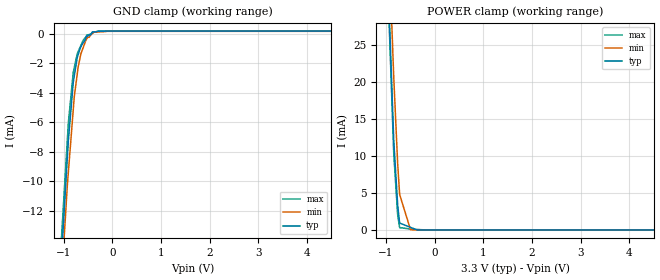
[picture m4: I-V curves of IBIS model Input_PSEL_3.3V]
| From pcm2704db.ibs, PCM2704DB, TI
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[Model] Input_PSEL_3.3V
Model_type Input
Vinl  = 800.000mV
Vinh  = 2.00000V
C_comp  2.00000pF 2.00000pF 2.00000pF
| variable   typ   min   max
[Voltage Range]   3.30000V  3.00000V  3.60000V
[POWER Clamp Reference]  3.30000V  3.00000V  3.60000V
[GND Clamp Reference]   0.00000V  0.00000V  0.00000V
[Temperature Range]   25   85   -25
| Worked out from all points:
|   GND clamp passes 1 mA (typ) near -0.66 V on its own axis
|   POWER clamp passes 1 mA (typ) near -0.72 V on its own axis
[GND Clamp]
-3.3V     -140.8mA   -139.2mA   -138.3mA
-921.7mV  -8.364mA   -10.23mA   -7.161mA
-901.3mV  -7.23mA    -9.374mA   -6.038mA
-800.6mV  -3.279mA   -5.128mA   -2.6mA
-780.4mV  -2.862mA   -4.278mA   -2.286mA
-719.6mV  -1.606mA   -2.734mA   -1.341mA
-699.5mV  -1.397mA   -2.223mA   -1.19mA
-643.7mV  -876uA     -1.341mA   -770.8uA
-542.3mV  -256.9uA   -435.1uA   -259.8uA
-405.9mV  142.7uA    36.77uA    117.8uA
-95.38mV  198.5uA    182.8uA    206.2uA
6.6V      198.5uA    182.8uA    206.2uA
[POWER Clamp]
-3.3V     465.9mA    458.7mA    514.8mA
-1.019V   44.81mA    52.21mA    43.33mA
-842.3mV  12.17mA    20.7mA     10.38mA
-761.5mV  3.389mA    8.982mA    2.054mA
-721.2mV  933.5uA    4.804mA    318.7uA
-498mV    355.7uA    48.92uA    133uA
-360.6mV  0A         0A         69.66uA
6.6V      0A         0A         0A
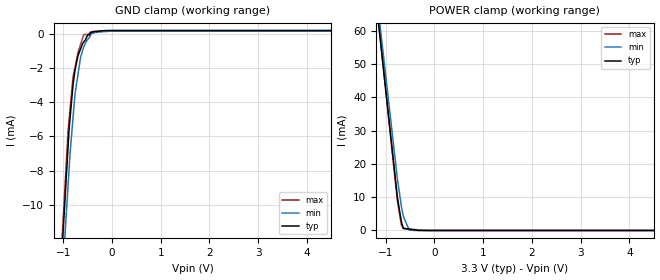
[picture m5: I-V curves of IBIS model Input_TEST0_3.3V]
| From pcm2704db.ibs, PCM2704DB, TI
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[Model] Input_TEST0_3.3V
Model_type Input
Vinl  = 800.000mV
Vinh  = 2.00000V
C_comp  2.00000pF 2.00000pF 2.00000pF
| variable   typ   min   max
[Voltage Range]   3.30000V  3.00000V  3.60000V
[POWER Clamp Reference]  3.30000V  3.00000V  3.60000V
[GND Clamp Reference]   0.00000V  0.00000V  0.00000V
[Temperature Range]   25   85   -25
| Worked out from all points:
|   GND clamp passes 1 mA (typ) near -0.66 V on its own axis
|   POWER clamp passes 1 mA (typ) near -0.65 V on its own axis
[GND Clamp]
-3.3V     -124.7mA   -119.3mA   -128.4mA
-901.3mV  -6.571mA   -8.863mA   -5.667mA
-881.1mV  -5.577mA   -7.934mA   -5.039mA
-861.1mV  -4.935mA   -7.015mA   -4.417mA
-800.5mV  -2.988mA   -4.931mA   -2.53mA
-760.1mV  -2.122mA   -3.541mA   -1.96mA
-699.4mV  -1.282mA   -2.4mA     -1.106mA
-643.8mV  -860.6uA   -1.353mA   -601.6uA
-580.5mV  -467.7uA   -757uA     -28.33uA
-421.2mV  94.21uA    52.16uA    143.9uA
-66.12mV  207.3uA    167.2uA    176.8uA
6.6V      209.8uA    167.2uA    176.8uA
[POWER Clamp]
-3.3V     352.4mA    343.7mA    367.6mA
-1.08V    52.9mA     56.66mA    53.18mA
-958.6mV  36.57mA    41mA       36.03mA
-761.5mV  9.983mA    15.52mA    8.882mA
-680.5mV  2.623mA    7.332mA    1.712mA
-640.2mV  655.4uA    4.295mA    570.9uA
-518.3mV  405.8uA    116.5uA    419.9uA
-402.2mV  168.1uA    0A         276.1uA
-120.3mV  0A         0A         0A
6.6V      0A         0A         0A
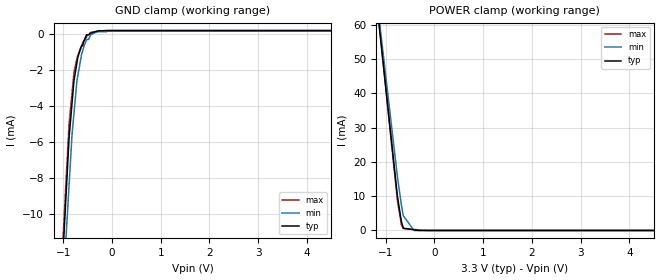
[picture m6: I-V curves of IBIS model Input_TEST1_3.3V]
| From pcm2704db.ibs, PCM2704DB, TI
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[Model] Input_TEST1_3.3V
Model_type Input
Vinl  = 800.000mV
Vinh  = 2.00000V
C_comp  2.00000pF 2.00000pF 2.00000pF
| variable   typ   min   max
[Voltage Range]   3.30000V  3.00000V  3.60000V
[POWER Clamp Reference]  3.30000V  3.00000V  3.60000V
[GND Clamp Reference]   0.00000V  0.00000V  0.00000V
[Temperature Range]   25   85   -25
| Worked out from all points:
|   GND clamp passes 1 mA (typ) near -0.67 V on its own axis
|   POWER clamp passes 1 mA (typ) near -0.65 V on its own axis
[GND Clamp]
-3.3V     -130.1mA   -120.2mA   -129.1mA
-881.1mV  -5.749mA   -8.392mA   -4.971mA
-820.9mV  -3.852mA   -5.606mA   -3.263mA
-780.4mV  -2.576mA   -4.398mA   -2.114mA
-719.6mV  -1.585mA   -2.584mA   -1.338mA
-699.4mV  -1.257mA   -2.276mA   -1.172mA
-623.6mV  -651uA     -1.115mA   -627.6uA
-522.1mV  -31.22uA   -324.1uA   -152.3uA
-479.1mV  -25.74uA   -291.7uA   -28.83uA
-441.3mV  53.78uA    -38.8uA    97.82uA
-30.79mV  207.9uA    173.6uA    180.3uA
6.6V      207.9uA    173.6uA    180.3uA
[POWER Clamp]
-3.3V     347.9mA    327.9mA    363.9mA
-1.08V    52.38mA    54.86mA    52.67mA
-958.6mV  36.26mA    39.97mA    35.7mA
-761.5mV  10.02mA    15.73mA    8.83mA
-680.5mV  2.655mA    7.556mA    1.705mA
-640.2mV  669.7uA    4.332mA    552.3uA
-422.1mV  213.4uA    904.5nA    290.9uA
-120.3mV  0A         0A         0A
6.6V      0A         0A         0A
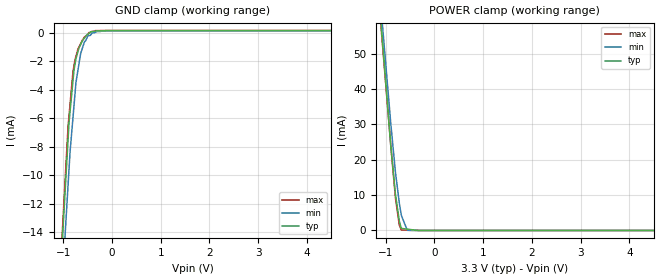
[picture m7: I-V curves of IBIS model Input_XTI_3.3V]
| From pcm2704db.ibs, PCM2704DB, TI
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[Model] Input_XTI_3.3V
Model_type Input
Vinl  = 800.000mV
Vinh  = 2.00000V
C_comp  2.00000pF 2.00000pF 2.00000pF
| variable   typ   min   max
[Voltage Range]   3.30000V  3.00000V  3.60000V
[POWER Clamp Reference]  3.30000V  3.00000V  3.60000V
[GND Clamp Reference]   0.00000V  0.00000V  0.00000V
[Temperature Range]   25   85   -25
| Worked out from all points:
|   GND clamp passes 1 mA (typ) near -0.67 V on its own axis
|   POWER clamp passes 1 mA (typ) near -0.69 V on its own axis
[GND Clamp]
-3.3V     -152.1mA   -148.1mA   -157.5mA
-901.3mV  -7.472mA   -10.69mA   -6.553mA
-881.1mV  -6.256mA   -9.536mA   -5.788mA
-861.1mV  -5.536mA   -8.39mA    -5.029mA
-800.5mV  -3.353mA   -5.942mA   -2.73mA
-780.4mV  -2.627mA   -5.128mA   -2.323mA
-739.7mV  -1.807mA   -3.484mA   -1.654mA
-643.7mV  -820.9uA   -1.452mA   -762.3uA
-562.2mV  -345uA     -602.3uA   -275.1uA
-416mV    83.3uA     -47.86uA   108.5uA
-91.58mV  164.2uA    149.3uA    170.6uA
6.6V      164.4uA    149.3uA    170.6uA
[POWER Clamp]
-3.3V     439.7mA    421.3mA    426.6mA
-1.12V    62.51mA    66.56mA    61.4mA
-1.039V   48.51mA    53.39mA    47.85mA
-897.8mV  24.04mA    30.38mA    24.16mA
-802.1mV  10.34mA    16.56mA    9.259mA
-721.2mV  2.588mA    7.664mA    1.467mA
-680.5mV  582.9uA    4.273mA    140.8uA
-559.2mV  375.1uA    64.49uA    60.06uA
-340.2mV  0A         0A         24.51uA
6.6V      0A         0A         0A
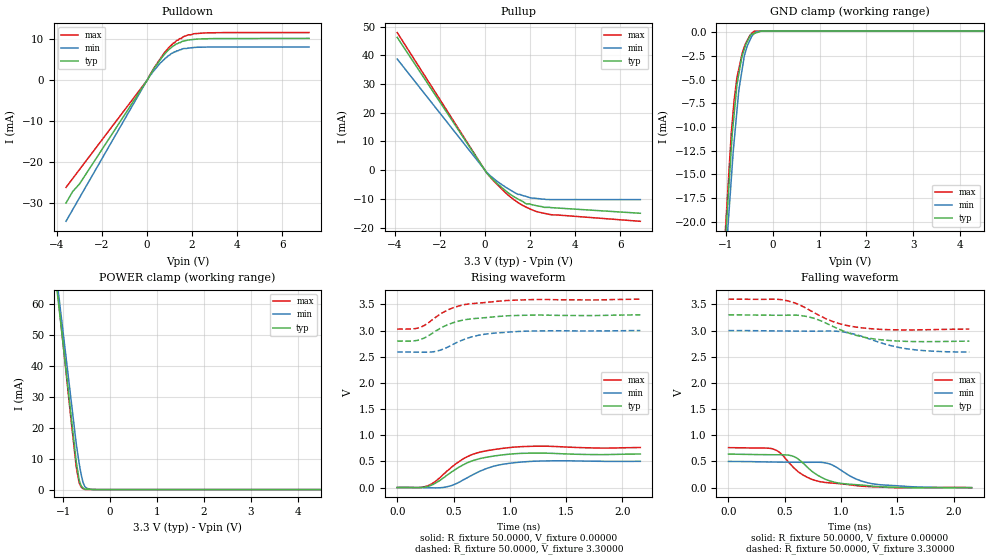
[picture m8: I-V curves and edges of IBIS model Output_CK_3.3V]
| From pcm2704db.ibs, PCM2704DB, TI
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[Model] Output_CK_3.3V
Model_type Output
Vref  = 0.00000V
Cref  = 2.00000pF
Vmeas = 1.65000V
C_comp  2.00000pF 2.00000pF 2.00000pF
| variable   typ   min   max
[Voltage Range]   3.30000V  3.00000V  3.60000V
[POWER Clamp Reference]  3.30000V  3.00000V  3.60000V
[Pullup Reference]   3.30000V  3.00000V  3.60000V
[Pulldown Reference]   0.00000V  0.00000V  0.00000V
[GND Clamp Reference]   0.00000V  0.00000V  0.00000V
[Temperature Range]   25   85   -25
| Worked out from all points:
|   slope of the pulldown table from 0 to 0.495 V, typ, clamps not added: 114 ohm
|   slope of the pullup table from 0 to 0.495 V, typ, clamps not added: 116 ohm
|   GND clamp passes 1 mA (typ) near -0.55 V on its own axis
|   POWER clamp passes 1 mA (typ) near -0.60 V on its own axis
|   rising waveform, R_fixture 50.0000, V_fixture 0.00000: 20-80 % time 296ps typ, 298ps min, 286ps max; typ from 0 V to 0.64 V
|   falling waveform, R_fixture 50.0000, V_fixture 0.00000: 20-80 % time 263ps typ, 275ps min, 265ps max; typ from 0.64 V to 0 V
|   falling waveform, R_fixture 50.0000, V_fixture 3.30000: 20-80 % time 347ps typ, 388ps min, 335ps max; typ from 3.3 V to 2.8 V
|   rising waveform, R_fixture 50.0000, V_fixture 3.30000: 20-80 % time 312ps typ, 307ps min, 303ps max; typ from 2.8 V to 3.3 V
[GND Clamp]
-3.3V     -198.8mA   -187mA     -207.8mA
-881.1mV  -12.31mA   -15.49mA   -10.64mA
-861.1mV  -10.77mA   -14.08mA   -9.489mA
-820.8mV  -8.675mA   -11.56mA   -7.169mA
-760.1mV  -5.523mA   -8.271mA   -4.759mA
-719.6mV  -4.376mA   -6.078mA   -3.836mA
-659mV    -2.662mA   -4.201mA   -2.457mA
-603.2mV  -1.796mA   -2.471mA   -1.534mA
-461.8mV  -223.6uA   -588.8uA   -189.1uA
-390.9mV  -110.6uA   -114.1uA   123uA
-110.6mV  144.4uA    171uA      162.2uA
6.6V      144.4uA    171uA      168.5uA
[Pulldown]
-3.6V     -29.93mA   -34.38mA   -26.13mA
-3.3V     -27.11mA   -31.52mA   -23.96mA
-3V       -25.3mA    -28.66mA   -21.79mA
20.8mV    92.19uA    132.4uA    70.78uA
299.7mV   2.737mA    2.231mA    2.811mA
800.2mV   6.424mA    5.253mA    6.883mA
941.6mV   7.269mA    5.945mA    7.724mA
1.179V    8.327mA    6.76mA     9.042mA
1.442V    9.105mA    7.336mA    10.09mA
2.079V    9.887mA    7.918mA    11.27mA
3.499V    10.1mA     8.032mA    11.56mA
7.2V      10.15mA    8.034mA    11.56mA
[Pullup]
-3.9V     46.25mA    38.7mA     47.92mA
77.9mV    -979.7uA   -778.3uA   -1.01mA
518.1mV   -4.475mA   -3.764mA   -4.807mA
1.079V    -8.156mA   -6.694mA   -9.023mA
1.459V    -10.03mA   -8.412mA   -11.24mA
1.83V     -11.72mA   -9.138mA   -12.89mA
1.979V    -11.72mA   -9.527mA   -13.42mA
2.297V    -12.39mA   -9.851mA   -14.42mA
2.899V    -13.01mA   -10.22mA   -15.45mA
6.9V      -14.99mA   -10.22mA   -17.79mA
[POWER Clamp]
-3.3V     358.2mA    346.1mA    380.2mA
-1.039V   52.01mA    55.59mA    52.39mA
-842.3mV  25.32mA    30.27mA    23.83mA
-721.1mV  8.907mA    14.7mA     7.145mA
-660.2mV  3.154mA    8.48mA     2.208mA
-619.9mV  1.299mA    5.074mA    839uA
-579.2mV  517uA      2.386mA    287uA
-538.6mV  143.5uA    950.4uA    53uA
-498mV    121.8uA    421.7uA    47.85uA
-381.7mV  59.89uA    0A         33.08uA
6.6V      0A         0A         0A
[Rising Waveform]
R_fixture = 50.0000
V_fixture = 0.00000
V_fixture_min = 0.00000
V_fixture_max = 0.00000
0s        0V         0V         0V
200ps     -1.758mV   -1.258mV   662uV
280ps     26.18mV    -4.232mV   41.31mV
440ps     231.7mV    12.93mV    310.7mV
580ps     426.6mV    137.2mV    540.7mV
680ps     519.7mV    253.5mV    641.9mV
800ps     581.3mV    368.8mV    704.8mV
940ps     624.4mV    445mV      749.3mV
1.2ns     656.8mV    500.8mV    787.6mV
2.16ns    640.5mV    500.6mV    764.5mV
[Falling Waveform]
R_fixture = 50.0000
V_fixture = 0.00000
V_fixture_min = 0.00000
V_fixture_max = 0.00000
0s        640.5mV    500.6mV    764.5mV
400ps     628.4mV    489.5mV    736.3mV
460ps     628mV      488mV      662.5mV
580ps     595mV      485.5mV    380mV
700ps     393.2mV    484.4mV    198.4mV
820ps     204.2mV    484.2mV    112.2mV
980ps     88.3mV     361.2mV    77.92mV
1.14ns    55.92mV    160mV      38.05mV
1.28ns    28.99mV    74.69mV    18.1mV
2.16ns    0V         0V         0V
[Falling Waveform]
R_fixture = 50.0000
V_fixture = 3.30000
V_fixture_min = 3.00000
V_fixture_max = 3.60000
0s        3.3V       3V         3.6V
460ps     3.292V     2.992V     3.592V
560ps     3.295V     2.99V      3.547V
680ps     3.274V     2.988V     3.439V
780ps     3.219V     2.988V     3.319V
920ps     3.087V     2.991V     3.178V
1.18ns    2.884V     2.894V     3.053V
1.4ns     2.815V     2.736V     3.019V
1.58ns    2.793V     2.654V     3.011V
2.14ns    2.798V     2.59V      3.027V
[Rising Waveform]
R_fixture = 50.0000
V_fixture = 3.30000
V_fixture_min = 3.00000
V_fixture_max = 3.60000
0s        2.798V     2.59V      3.027V
120ps     2.799V     2.589V     3.029V
200ps     2.823V     2.586V     3.057V
260ps     2.879V     2.586V     3.122V
340ps     2.989V     2.601V     3.25V
480ps     3.136V     2.718V     3.421V
640ps     3.218V     2.864V     3.509V
800ps     3.249V     2.937V     3.54V
1.12ns    3.291V     2.986V     3.586V
2.16ns    3.3V       3V         3.6V
[Ramp]
| variable typ   min   max
dV/dt_r   385.913m/420.508p  299.431m/472.835p  458.492m/391.970p
dV/dt_f   303.401m/426.304p  240.705m/473.539p  346.365m/394.914p
R_load  =  50.0000Ohms
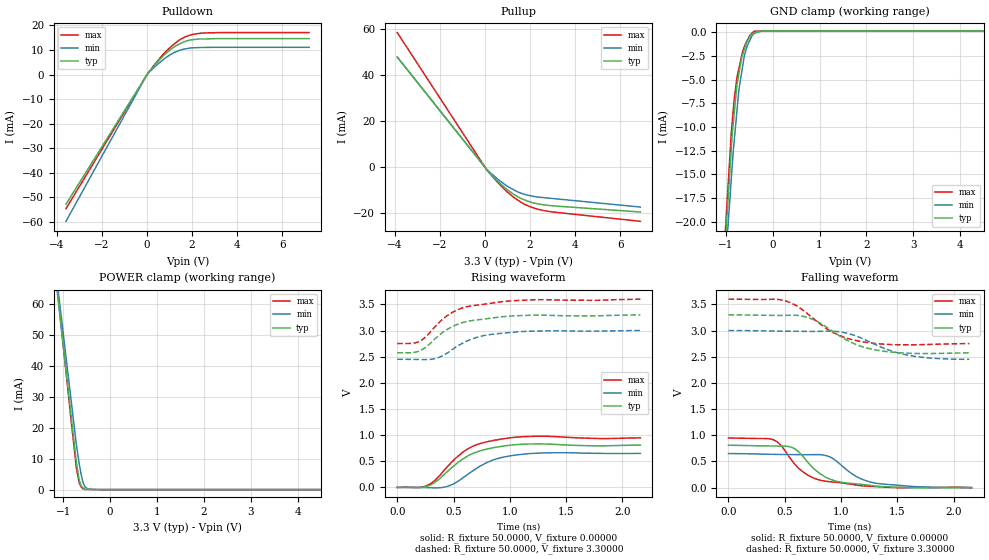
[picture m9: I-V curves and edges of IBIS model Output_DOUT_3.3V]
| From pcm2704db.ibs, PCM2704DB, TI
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[Model] Output_DOUT_3.3V
Model_type Output
Vref  = 0.00000V
Cref  = 2.00000pF
Vmeas = 1.65000V
C_comp  2.00000pF 2.00000pF 2.00000pF
| variable   typ   min   max
[Voltage Range]   3.30000V  3.00000V  3.60000V
[POWER Clamp Reference]  3.30000V  3.00000V  3.60000V
[Pullup Reference]   3.30000V  3.00000V  3.60000V
[Pulldown Reference]   0.00000V  0.00000V  0.00000V
[GND Clamp Reference]   0.00000V  0.00000V  0.00000V
[Temperature Range]   25   85   -25
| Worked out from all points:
|   slope of the pulldown table from 0 to 0.495 V, typ, clamps not added: 91 ohm
|   slope of the pullup table from 0 to 0.495 V, typ, clamps not added: 93 ohm
|   GND clamp passes 1 mA (typ) near -0.55 V on its own axis
|   POWER clamp passes 1 mA (typ) near -0.60 V on its own axis
|   rising waveform, R_fixture 50.0000, V_fixture 0.00000: 20-80 % time 296ps typ, 298ps min, 286ps max; typ from 0 V to 0.81 V
|   falling waveform, R_fixture 50.0000, V_fixture 0.00000: 20-80 % time 263ps typ, 275ps min, 265ps max; typ from 0.81 V to 0 V
|   falling waveform, R_fixture 50.0000, V_fixture 3.30000: 20-80 % time 347ps typ, 388ps min, 335ps max; typ from 3.3 V to 2.57 V
|   rising waveform, R_fixture 50.0000, V_fixture 3.30000: 20-80 % time 312ps typ, 307ps min, 303ps max; typ from 2.57 V to 3.3 V
[GND Clamp]
-3.3V     -198.8mA   -187mA     -207.8mA
-881.1mV  -12.31mA   -15.49mA   -10.64mA
-861.1mV  -10.77mA   -14.08mA   -9.489mA
-820.8mV  -8.675mA   -11.56mA   -7.169mA
-760.1mV  -5.523mA   -8.271mA   -4.759mA
-719.6mV  -4.376mA   -6.078mA   -3.836mA
-659mV    -2.662mA   -4.201mA   -2.457mA
-603.2mV  -1.796mA   -2.471mA   -1.534mA
-461.8mV  -223.6uA   -588.8uA   -189.1uA
-390.9mV  -110.6uA   -114.1uA   123uA
-110.6mV  144.4uA    171uA      162.2uA
6.6V      144.4uA    171uA      168.5uA
[Pulldown]
-3.6V     -52.77mA   -59.72mA   -54.59mA
186.8uV   -32.36uA   39.2uA     -24.78uA
340.3mV   3.865mA    3.081mA    4.108mA
800.3mV   8.288mA    6.674mA    9.033mA
1.119V    10.71mA    8.531mA    11.8mA
1.523V    12.81mA    10.07mA    14.55mA
1.78V     13.78mA    10.59mA    15.65mA
2.261V    14.44mA    10.97mA    16.72mA
3.317V    14.63mA    11.1mA     17.09mA
7.2V      14.63mA    11.1mA     17.1mA
[Pullup]
-3.9V     47.66mA    47.79mA    58.36mA
77.7mV    -1.111mA   -954.5uA   -1.163mA
761.3mV   -7.948mA   -6.718mA   -8.61mA
1.281V    -11.86mA   -9.89mA    -13.18mA
1.661V    -13.88mA   -11.54mA   -15.64mA
1.938V    -14.91mA   -12.28mA   -16.94mA
2.621V    -16.41mA   -13.28mA   -18.9mA
6.9V      -19.51mA   -17.35mA   -23.53mA
[POWER Clamp]
-3.3V     358.2mA    346.1mA    380.2mA
-1.039V   52.01mA    55.59mA    52.39mA
-842.3mV  25.32mA    30.27mA    23.83mA
-721.1mV  8.907mA    14.7mA     7.145mA
-660.2mV  3.154mA    8.48mA     2.208mA
-619.9mV  1.299mA    5.074mA    839uA
-579.2mV  517uA      2.386mA    287uA
-538.6mV  143.5uA    950.4uA    53uA
-498mV    121.8uA    421.7uA    47.85uA
-381.7mV  59.89uA    0A         33.08uA
6.6V      0A         0A         0A
[Rising Waveform]
R_fixture = 50.0000
V_fixture = 0.00000
V_fixture_min = 0.00000
V_fixture_max = 0.00000
0s        0V         0V         0V
200ps     -2.222mV   -1.634mV   820.6uV
280ps     33.09mV    -5.496mV   51.21mV
440ps     292.8mV    16.79mV    385.2mV
580ps     539.2mV    178.1mV    670.3mV
680ps     657mV      329.1mV    795.8mV
800ps     734.8mV    478.8mV    873.8mV
940ps     789.3mV    577.9mV    928.9mV
1.2ns     830.2mV    650.2mV    976.5mV
2.16ns    809.6mV    650mV      947.8mV
[Falling Waveform]
R_fixture = 50.0000
V_fixture = 0.00000
V_fixture_min = 0.00000
V_fixture_max = 0.00000
0s        809.6mV    650mV      947.8mV
400ps     794.3mV    635.6mV    912.7mV
460ps     793.8mV    633.6mV    821.4mV
580ps     752.1mV    630.4mV    471.1mV
700ps     497mV      629mV      246mV
820ps     258.1mV    628.7mV    139.1mV
980ps     111.6mV    469mV      96.6mV
1.14ns    70.68mV    207.7mV    47.18mV
1.28ns    36.65mV    96.98mV    22.44mV
2.16ns    0V         0V         0V
[Falling Waveform]
R_fixture = 50.0000
V_fixture = 3.30000
V_fixture_min = 3.00000
V_fixture_max = 3.60000
0s        3.3V       3V         3.6V
420ps     3.289V     2.99V      3.597V
520ps     3.29V      2.988V     3.555V
620ps     3.288V     2.985V     3.453V
760ps     3.204V     2.983V     3.219V
980ps     2.907V     2.978V     2.91V
1.18ns    2.698V     2.857V     2.789V
1.4ns     2.599V     2.646V     2.738V
1.58ns    2.568V     2.535V     2.727V
2.14ns    2.575V     2.45V      2.75V
[Rising Waveform]
R_fixture = 50.0000
V_fixture = 3.30000
V_fixture_min = 3.00000
V_fixture_max = 3.60000
0s        2.575V     2.45V      2.75V
120ps     2.575V     2.448V     2.753V
200ps     2.61V      2.445V     2.795V
260ps     2.692V     2.444V     2.891V
340ps     2.85V      2.465V     3.081V
480ps     3.063V     2.622V     3.334V
640ps     3.182V     2.818V     3.465V
800ps     3.227V     2.915V     3.511V
1.12ns    3.287V     2.982V     3.579V
2.16ns    3.3V       3V         3.6V
[Ramp]
| variable typ   min   max
dV/dt_r   485.428m/420.508p  391.096m/472.835p  568.419m/391.970p
dV/dt_f   437.666m/426.304p  331.922m/473.539p  510.586m/394.914p
R_load  =  50.0000Ohms
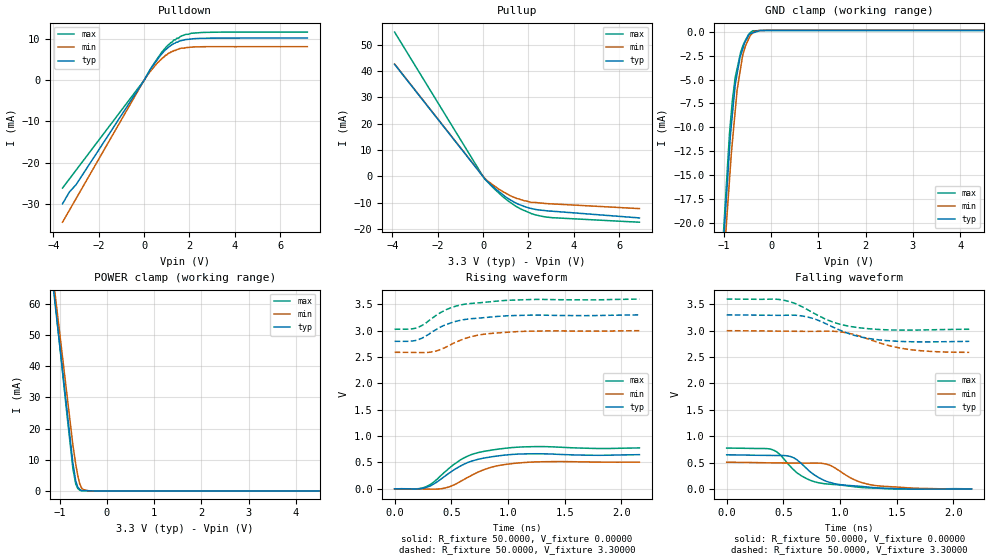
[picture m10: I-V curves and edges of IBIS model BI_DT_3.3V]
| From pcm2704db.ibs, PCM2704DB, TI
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[Model] BI_DT_3.3V
Model_type I/O
Vinl  = 800.000mV
Vinh  = 2.00000V
Vref  = 0.00000V
Cref  = 2.00000pF
Vmeas = 1.65000V
C_comp  2.00000pF 2.00000pF 2.00000pF
| variable   typ   min   max
[Voltage Range]   3.30000V  3.00000V  3.60000V
[POWER Clamp Reference]  3.30000V  3.00000V  3.60000V
[Pullup Reference]   3.30000V  3.00000V  3.60000V
[Pulldown Reference]   0.00000V  0.00000V  0.00000V
[GND Clamp Reference]   0.00000V  0.00000V  0.00000V
[Temperature Range]   25   85   -25
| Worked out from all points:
|   slope of the pulldown table from 0 to 0.495 V, typ, clamps not added: 114 ohm
|   slope of the pullup table from 0 to 0.495 V, typ, clamps not added: 116 ohm
|   GND clamp passes 1 mA (typ) near -0.55 V on its own axis
|   POWER clamp passes 1 mA (typ) near -0.60 V on its own axis
|   rising waveform, R_fixture 50.0000, V_fixture 0.00000: 20-80 % time 296ps typ, 298ps min, 286ps max; typ from 0 V to 0.648 V
|   falling waveform, R_fixture 50.0000, V_fixture 0.00000: 20-80 % time 263ps typ, 275ps min, 265ps max; typ from 0.648 V to 0 V
|   falling waveform, R_fixture 50.0000, V_fixture 3.30000: 20-80 % time 347ps typ, 388ps min, 335ps max; typ from 3.3 V to 2.8 V
|   rising waveform, R_fixture 50.0000, V_fixture 3.30000: 20-80 % time 312ps typ, 307ps min, 303ps max; typ from 2.8 V to 3.3 V
[GND Clamp]
-3.3V     -198.8mA   -187mA     -207.8mA
-881.1mV  -12.31mA   -15.49mA   -10.64mA
-861.1mV  -10.77mA   -14.08mA   -9.489mA
-820.8mV  -8.675mA   -11.56mA   -7.169mA
-760.1mV  -5.523mA   -8.271mA   -4.759mA
-719.6mV  -4.376mA   -6.078mA   -3.836mA
-659mV    -2.662mA   -4.201mA   -2.457mA
-603.2mV  -1.796mA   -2.471mA   -1.534mA
-461.8mV  -223.6uA   -588.8uA   -189.1uA
-390.9mV  -110.6uA   -114.1uA   123uA
-110.6mV  144.4uA    171uA      162.2uA
6.6V      144.4uA    171uA      168.5uA
[Pulldown]
-3.6V     -29.93mA   -34.38mA   -26.13mA
-3.3V     -27.11mA   -31.52mA   -23.96mA
-3V       -25.3mA    -28.66mA   -21.79mA
20.8mV    92.19uA    132.4uA    70.78uA
299.7mV   2.737mA    2.231mA    2.811mA
800.2mV   6.424mA    5.253mA    6.883mA
941.6mV   7.269mA    5.945mA    7.724mA
1.179V    8.327mA    6.76mA     9.042mA
1.442V    9.105mA    7.336mA    10.09mA
2.079V    9.887mA    7.918mA    11.27mA
3.499V    10.1mA     8.032mA    11.56mA
7.2V      10.15mA    8.034mA    11.56mA
[Pullup]
-3.9V     42.53mA    42.65mA    54.78mA
0V        -82.33uA   20.74uA    -14.22uA
179.3mV   -1.837mA   -1.58mA    -1.929mA
478.1mV   -4.227mA   -3.543mA   -4.596mA
1.039V    -8.041mA   -6.567mA   -8.869mA
1.459V    -10.16mA   -8.298mA   -11.43mA
1.79V     -11.41mA   -9.183mA   -12.89mA
2.257V    -12.47mA   -9.921mA   -14.51mA
2.778V    -13.05mA   -10.35mA   -15.46mA
6.9V      -15.8mA    -12.27mA   -17.43mA
[POWER Clamp]
-3.3V     358.2mA    346.1mA    380.2mA
-1.039V   52.01mA    55.59mA    52.39mA
-842.3mV  25.32mA    30.27mA    23.83mA
-721.1mV  8.907mA    14.7mA     7.145mA
-660.2mV  3.154mA    8.48mA     2.208mA
-619.9mV  1.299mA    5.074mA    839uA
-579.2mV  517uA      2.386mA    287uA
-538.6mV  143.5uA    950.4uA    53uA
-498mV    121.8uA    421.7uA    47.85uA
-381.7mV  59.89uA    0A         33.08uA
6.6V      0A         0A         0A
[Rising Waveform]
R_fixture = 50.0000
V_fixture = 0.00000
V_fixture_min = 0.00000
V_fixture_max = 0.00000
0s        0V         0V         0V
200ps     -1.778mV   -1.272mV   671.5uV
280ps     26.47mV    -4.28mV    41.9mV
440ps     234.3mV    13.08mV    315.2mV
580ps     431.4mV    138.7mV    548.5mV
680ps     525.6mV    256.3mV    651.2mV
800ps     587.8mV    372.9mV    715mV
940ps     631.5mV    450.1mV    760.2mV
1.2ns     664.2mV    506.4mV    799.1mV
2.16ns    647.7mV    506.2mV    775.6mV
[Falling Waveform]
R_fixture = 50.0000
V_fixture = 0.00000
V_fixture_min = 0.00000
V_fixture_max = 0.00000
0s        647.7mV    506.2mV    775.6mV
400ps     635.4mV    495mV      746.9mV
460ps     635mV      493.5mV    672.1mV
580ps     601.7mV    490.9mV    385.5mV
700ps     397.6mV    489.9mV    201.3mV
820ps     206.5mV    489.6mV    113.8mV
980ps     89.29mV    365.3mV    79.05mV
1.14ns    56.55mV    161.8mV    38.61mV
1.28ns    29.32mV    75.53mV    18.37mV
2.16ns    0V         0V         0V
[Falling Waveform]
R_fixture = 50.0000
V_fixture = 3.30000
V_fixture_min = 3.00000
V_fixture_max = 3.60000
0s        3.3V       3V         3.6V
460ps     3.292V     2.992V     3.592V
560ps     3.295V     2.99V      3.547V
680ps     3.274V     2.988V     3.439V
780ps     3.219V     2.988V     3.319V
920ps     3.087V     2.991V     3.178V
1.18ns    2.884V     2.894V     3.053V
1.4ns     2.815V     2.736V     3.019V
1.58ns    2.793V     2.654V     3.011V
2.14ns    2.798V     2.59V      3.027V
[Rising Waveform]
R_fixture = 50.0000
V_fixture = 3.30000
V_fixture_min = 3.00000
V_fixture_max = 3.60000
0s        2.798V     2.59V      3.027V
120ps     2.799V     2.589V     3.029V
200ps     2.823V     2.586V     3.057V
260ps     2.879V     2.586V     3.122V
340ps     2.989V     2.601V     3.25V
480ps     3.136V     2.718V     3.421V
640ps     3.218V     2.864V     3.509V
800ps     3.249V     2.937V     3.54V
1.12ns    3.291V     2.986V     3.586V
2.16ns    3.3V       3V         3.6V
[Ramp]
| variable typ   min   max
dV/dt_r   386.302m/420.508p  302.371m/472.835p  463.460m/391.970p
dV/dt_f   303.967m/426.304p  240.198m/473.539p  345.648m/394.914p
R_load  =  50.0000Ohms
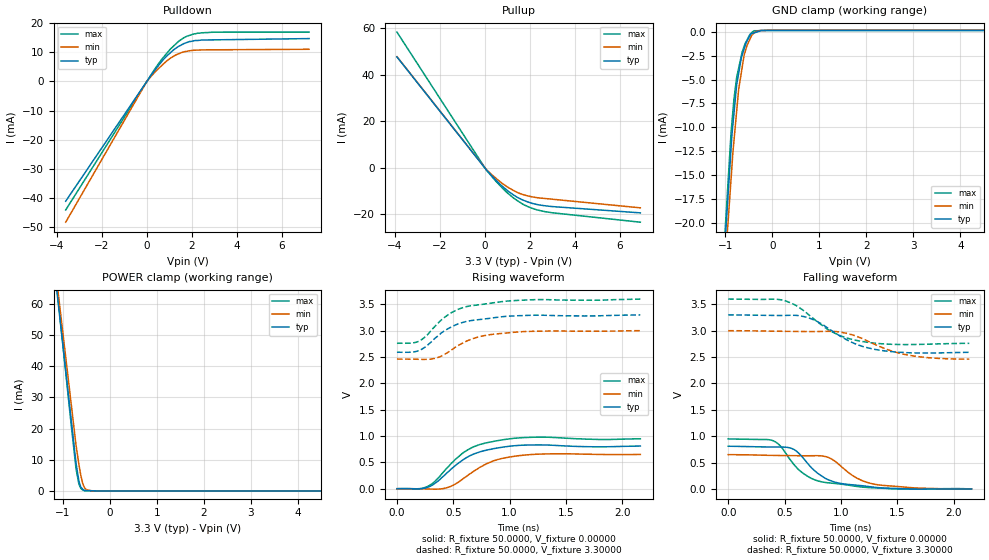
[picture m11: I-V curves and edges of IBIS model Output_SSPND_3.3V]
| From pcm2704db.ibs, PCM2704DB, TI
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[Model] Output_SSPND_3.3V
Model_type Output
Vref  = 0.00000V
Cref  = 2.00000pF
Vmeas = 1.65000V
C_comp  2.00000pF 2.00000pF 2.00000pF
| variable   typ   min   max
[Voltage Range]   3.30000V  3.00000V  3.60000V
[POWER Clamp Reference]  3.30000V  3.00000V  3.60000V
[Pullup Reference]   3.30000V  3.00000V  3.60000V
[Pulldown Reference]   0.00000V  0.00000V  0.00000V
[GND Clamp Reference]   0.00000V  0.00000V  0.00000V
[Temperature Range]   25   85   -25
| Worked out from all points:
|   slope of the pulldown table from 0 to 0.495 V, typ, clamps not added: 94.8 ohm
|   slope of the pullup table from 0 to 0.495 V, typ, clamps not added: 93 ohm
|   GND clamp passes 1 mA (typ) near -0.55 V on its own axis
|   POWER clamp passes 1 mA (typ) near -0.60 V on its own axis
|   rising waveform, R_fixture 50.0000, V_fixture 0.00000: 20-80 % time 296ps typ, 298ps min, 286ps max; typ from 0 V to 0.81 V
|   falling waveform, R_fixture 50.0000, V_fixture 0.00000: 20-80 % time 263ps typ, 275ps min, 265ps max; typ from 0.81 V to 0 V
|   falling waveform, R_fixture 50.0000, V_fixture 3.30000: 20-80 % time 347ps typ, 388ps min, 335ps max; typ from 3.3 V to 2.59 V
|   rising waveform, R_fixture 50.0000, V_fixture 3.30000: 20-80 % time 312ps typ, 307ps min, 303ps max; typ from 2.59 V to 3.3 V
[GND Clamp]
-3.3V     -198.8mA   -187mA     -207.8mA
-881.1mV  -12.31mA   -15.49mA   -10.64mA
-861.1mV  -10.77mA   -14.08mA   -9.489mA
-820.8mV  -8.675mA   -11.56mA   -7.169mA
-760.1mV  -5.523mA   -8.271mA   -4.759mA
-719.6mV  -4.376mA   -6.078mA   -3.836mA
-659mV    -2.662mA   -4.201mA   -2.457mA
-603.2mV  -1.796mA   -2.471mA   -1.534mA
-461.8mV  -223.6uA   -588.8uA   -189.1uA
-390.9mV  -110.6uA   -114.1uA   123uA
-110.6mV  144.4uA    171uA      162.2uA
6.6V      144.4uA    171uA      168.5uA
[Pulldown]
-3.6V     -41.05mA   -48.24mA   -44.05mA
21.12mV   254uA      280.7uA    205.7uA
340.3mV   3.68mA     3.021mA    4.107mA
719.3mV   7.378mA    5.865mA    8.108mA
1.063V    9.954mA    8.067mA    11.23mA
1.382V    11.9mA     9.382mA    13.54mA
1.619V    12.87mA    10.07mA    14.87mA
1.902V    13.7mA     10.53mA    15.82mA
2.241V    14.05mA    10.74mA    16.52mA
3.439V    14.31mA    10.86mA    16.92mA
7.2V      14.69mA    11.03mA    16.92mA
[Pullup]
-3.9V     47.66mA    47.79mA    58.36mA
77.7mV    -1.111mA   -954.5uA   -1.163mA
761.3mV   -7.948mA   -6.718mA   -8.61mA
1.281V    -11.86mA   -9.89mA    -13.18mA
1.661V    -13.88mA   -11.54mA   -15.64mA
1.938V    -14.91mA   -12.28mA   -16.94mA
2.621V    -16.41mA   -13.28mA   -18.9mA
6.9V      -19.51mA   -17.35mA   -23.53mA
[POWER Clamp]
-3.3V     358.2mA    346.1mA    380.2mA
-1.039V   52.01mA    55.59mA    52.39mA
-842.3mV  25.32mA    30.27mA    23.83mA
-721.1mV  8.907mA    14.7mA     7.145mA
-660.2mV  3.154mA    8.48mA     2.208mA
-619.9mV  1.299mA    5.074mA    839uA
-579.2mV  517uA      2.386mA    287uA
-538.6mV  143.5uA    950.4uA    53uA
-498mV    121.8uA    421.7uA    47.85uA
-381.7mV  59.89uA    0A         33.08uA
6.6V      0A         0A         0A
[Rising Waveform]
R_fixture = 50.0000
V_fixture = 0.00000
V_fixture_min = 0.00000
V_fixture_max = 0.00000
0s        0V         0V         0V
200ps     -2.222mV   -1.634mV   820.6uV
280ps     33.09mV    -5.496mV   51.21mV
440ps     292.8mV    16.79mV    385.2mV
580ps     539.2mV    178.1mV    670.3mV
680ps     657mV      329.1mV    795.8mV
800ps     734.8mV    478.8mV    873.8mV
940ps     789.3mV    577.9mV    928.9mV
1.2ns     830.2mV    650.2mV    976.5mV
2.16ns    809.6mV    650mV      947.8mV
[Falling Waveform]
R_fixture = 50.0000
V_fixture = 0.00000
V_fixture_min = 0.00000
V_fixture_max = 0.00000
0s        809.6mV    650mV      947.8mV
400ps     794.3mV    635.6mV    912.7mV
460ps     793.8mV    633.6mV    821.4mV
580ps     752.1mV    630.4mV    471.1mV
700ps     497mV      629mV      246mV
820ps     258.1mV    628.7mV    139.1mV
980ps     111.6mV    469mV      96.6mV
1.14ns    70.68mV    207.7mV    47.18mV
1.28ns    36.65mV    96.98mV    22.44mV
2.16ns    0V         0V         0V
[Falling Waveform]
R_fixture = 50.0000
V_fixture = 3.30000
V_fixture_min = 3.00000
V_fixture_max = 3.60000
0s        3.3V       3V         3.6V
420ps     3.289V     2.991V     3.597V
520ps     3.29V      2.988V     3.556V
620ps     3.288V     2.986V     3.455V
760ps     3.206V     2.984V     3.224V
980ps     2.916V     2.978V     2.918V
1.18ns    2.711V     2.86V      2.799V
1.4ns     2.615V     2.652V     2.748V
1.58ns    2.584V     2.545V     2.737V
2.14ns    2.59V      2.461V     2.76V
[Rising Waveform]
R_fixture = 50.0000
V_fixture = 3.30000
V_fixture_min = 3.00000
V_fixture_max = 3.60000
0s        2.59V      2.461V     2.76V
120ps     2.591V     2.459V     2.763V
200ps     2.625V     2.456V     2.804V
260ps     2.705V     2.455V     2.899V
340ps     2.86V      2.476V     3.087V
460ps     3.046V     2.599V     3.312V
640ps     3.184V     2.821V     3.466V
800ps     3.228V     2.917V     3.512V
1.1ns     3.285V     2.979V     3.577V
2.16ns    3.3V       3V         3.6V
[Ramp]
| variable typ   min   max
dV/dt_r   486.285m/420.508p  390.462m/472.835p  567.914m/391.970p
dV/dt_f   429.490m/426.304p  325.122m/473.539p  504.612m/394.914p
R_load  =  50.0000Ohms
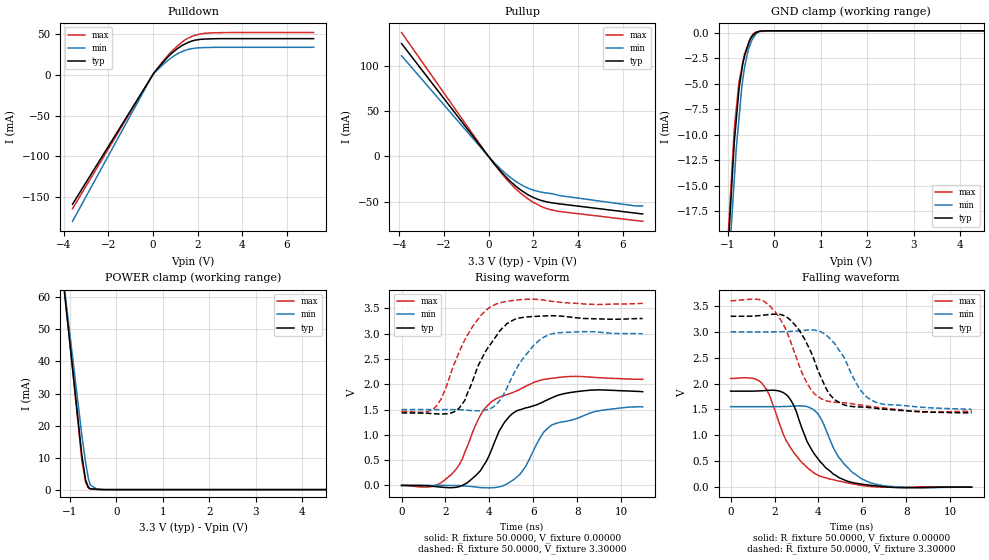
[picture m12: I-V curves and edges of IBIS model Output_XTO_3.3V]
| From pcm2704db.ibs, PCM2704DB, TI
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[Model] Output_XTO_3.3V
Model_type Output
Vref  = 0.00000V
Cref  = 2.00000pF
Vmeas = 1.65000V
C_comp  2.00000pF 2.00000pF 2.00000pF
| variable   typ   min   max
[Voltage Range]   3.30000V  3.00000V  3.60000V
[POWER Clamp Reference]  3.30000V  3.00000V  3.60000V
[Pullup Reference]   3.30000V  3.00000V  3.60000V
[Pulldown Reference]   0.00000V  0.00000V  0.00000V
[GND Clamp Reference]   0.00000V  0.00000V  0.00000V
[Temperature Range]   25   85   -25
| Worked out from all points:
|   slope of the pulldown table from 0 to 0.495 V, typ, clamps not added: 30.3 ohm
|   slope of the pullup table from 0 to 0.495 V, typ, clamps not added: 33.2 ohm
|   GND clamp passes 1 mA (typ) near -0.55 V on its own axis
|   POWER clamp passes 1 mA (typ) near -0.61 V on its own axis
|   rising waveform, R_fixture 50.0000, V_fixture 0.00000: 20-80 % time 1.58ns typ, 1.62ns min, 1.54ns max; typ from 0 V to 1.85 V
|   falling waveform, R_fixture 50.0000, V_fixture 0.00000: 20-80 % time 1.37ns typ, 1.27ns min, 1.53ns max; typ from 1.85 V to 0 V
|   falling waveform, R_fixture 50.0000, V_fixture 3.30000: 20-80 % time 1.21ns typ, 1.2ns min, 1.3ns max; typ from 3.3 V to 1.44 V
|   rising waveform, R_fixture 50.0000, V_fixture 3.30000: 20-80 % time 1.28ns typ, 1.24ns min, 1.31ns max; typ from 1.44 V to 3.3 V
[GND Clamp]
-3.3V     -202.3mA   -188.4mA   -204.3mA
-861.2mV  -10.72mA   -14.36mA   -9.41mA
-820.9mV  -8.663mA   -11.49mA   -7.586mA
-760.1mV  -5.554mA   -8.402mA   -4.835mA
-699.5mV  -3.669mA   -5.325mA   -3.426mA
-643.8mV  -2.39mA    -3.477mA   -2.13mA
-562.3mV  -1.186mA   -1.697mA   -1.114mA
-502mV    -524.1uA   -970uA     -443.3uA
-421mV    -152uA     -289.9uA   1.582uA
-310.9mV  131.6uA    135.8uA    112.4uA
-181.8mV  165.3uA    158.2uA    136.9uA
6.6V      176.1uA    158.9uA    160.8uA
[Pulldown]
-3.6V     -158.3mA   -179.2mA   -163.8mA
186.8uV   -97.06uA   117.6uA    -74.31uA
340.3mV   11.59mA    9.244mA    12.32mA
800.3mV   24.86mA    20.02mA    27.1mA
1.119V    32.12mA    25.59mA    35.41mA
1.523V    38.44mA    30.13mA    43.64mA
1.78V     41.33mA    31.82mA    46.9mA
2.261V    43.24mA    32.93mA    50.17mA
3.02V     43.87mA    33.31mA    51.21mA
7.2V      43.88mA    33.31mA    51.3mA
[Pullup]
-3.9V     124.7mA    111.3mA    136.9mA
0V        -42.82uA   -144.4uA   -241.5uA
639.7mV   -19.07mA   -16.17mA   -20.33mA
998.3mV   -28.09mA   -23.67mA   -30.34mA
1.459V    -37.31mA   -31.23mA   -41.11mA
2.02V     -45.52mA   -37.3mA    -50.84mA
2.379V    -48.71mA   -39.47mA   -55.54mA
2.919V    -51.45mA   -41.51mA   -59.62mA
3.178V    -52.33mA   -43.21mA   -60.78mA
6.3V      -61.74mA   -53.69mA   -69.89mA
6.9V      -63.55mA   -54.63mA   -71.61mA
[POWER Clamp]
-3.3V     358.5mA    330.7mA    375.2mA
-1.039V   51.39mA    53.61mA    51.84mA
-741.1mV  10.88mA    17.07mA    9.188mA
-660.1mV  3.071mA    8.621mA    2.296mA
-599.6mV  727.7uA    3.402mA    494.6uA
-559.1mV  265uA      1.442mA    152.2uA
-402.1mV  116.2uA    5.961uA    32.75uA
6.6V      0A         0A         0A
[Rising Waveform]
R_fixture = 50.0000
V_fixture = 0.00000
V_fixture_min = 0.00000
V_fixture_max = 0.00000
0s        0V         0V         0V
1.44ns    -18.72mV   -236.2uV   -15.81mV
2.28ns    -44.94mV   -299.1uV   220.8mV
2.76ns    -2.002mV   -6.24mV    515.3mV
3.6ns     295.8mV    -42.69mV   1.395V
4.44ns    1.07V      -30.27mV   1.74V
5.4ns     1.497V     223.9mV    1.903V
6.36ns    1.634V     975mV      2.086V
6.84ns    1.732V     1.195V     2.12V
10.98ns   1.853V     1.553V     2.098V
[Falling Waveform]
R_fixture = 50.0000
V_fixture = 0.00000
V_fixture_min = 0.00000
V_fixture_max = 0.00000
0s        1.853V     1.553V     2.098V
1.44ns    1.861V     1.552V     1.998V
1.8ns     1.87V      1.554V     1.743V
2.52ns    1.792V     1.557V     907.6mV
3.24ns    1.147V     1.567V     475.9mV
3.96ns    558.7mV    1.424V     232.7mV
4.92ns    187.5mV    577.9mV    117.2mV
6ns       53.56mV    153.1mV    30.72mV
7.32ns    -4.101mV   11.57mV    -2.525mV
10.98ns   0V         0V         0V
[Falling Waveform]
R_fixture = 50.0000
V_fixture = 3.30000
V_fixture_min = 3.00000
V_fixture_max = 3.60000
0s        3.3V       3V         3.6V
1.56ns    3.323V     2.998V     3.579V
2.16ns    3.339V     3V         3.309V
2.64ns    3.256V     3.004V     2.911V
3.48ns    2.765V     3.033V     2.009V
4.32ns    1.933V     2.945V     1.668V
5.04ns    1.608V     2.586V     1.632V
5.88ns    1.547V     1.888V     1.587V
6.6ns     1.522V     1.64V      1.546V
10.98ns   1.435V     1.5V       1.466V
[Rising Waveform]
R_fixture = 50.0000
V_fixture = 3.30000
V_fixture_min = 3.00000
V_fixture_max = 3.60000
0s        1.435V     1.5V       1.466V
1.56ns    1.417V     1.5V       1.557V
2.52ns    1.484V     1.499V     2.525V
2.88ns    1.68V      1.491V     2.877V
3.36ns    2.216V     1.476V     3.216V
4.32ns    2.958V     1.607V     3.591V
4.8ns     3.199V     1.929V     3.642V
5.64ns    3.328V     2.57V      3.68V
6.72ns    3.355V     2.984V     3.649V
10.98ns   3.3V       3V         3.6V
[Ramp]
| variable typ   min   max
dV/dt_r   1.11148/1.60590n  932.581m/1.59485n  1.25728/1.60414n
dV/dt_f   1.11850/1.23529n  901.541m/1.22682n  1.28270/1.27731n
R_load  =  50.0000Ohms
